# PKP2 V1.04 DRC semantic alignment, 2026-10-13.
# M1 routing PITCH stays 28nm (112nm at4x); cell M1 columns stay42nm.
# M0-M13 corner spacing is Euclidean CORNERTOCORNER, not MAXXY.
# Engineering AREA, array pitches and BSC conservative spacing are retained.
VERSION 5.8 ;
BUSBITCHARS "[]" ;
DIVIDERCHAR "/" ;
USEMINSPACING OBS OFF ;
CLEARANCEMEASURE EUCLIDEAN ;

PROPERTYDEFINITIONS
  LAYER LEF58_BACKSIDE STRING ;
  LAYER LEF58_PITCH STRING ;
  LAYER LEF58_CUTCLASS STRING ;
  LAYER LEF58_SPACINGTABLE STRING ;
  LAYER LEF58_ENCLOSURE STRING ;
  LAYER LEF58_CORNERSPACING STRING ;
  LAYER LEF58_RECTONLY STRING ;
  LAYER LEF58_RIGHTWAYONGRIDONLY STRING ;
  LAYER LEF58_TYPE STRING ;
  LAYER LEF58_SPACING STRING ;
  LAYER LEF58_WIDTH STRING ;
END PROPERTYDEFINITIONS

UNITS
  DATABASE MICRONS 2000 ;
END UNITS
MANUFACTURINGGRID 0.0005 ;

SITE CoreSite
  SIZE 0.042 BY 0.094 ;
  CLASS CORE ;
  SYMMETRY Y ;
END CoreSite

LAYER OVERLAP
  TYPE OVERLAP ;
END OVERLAP

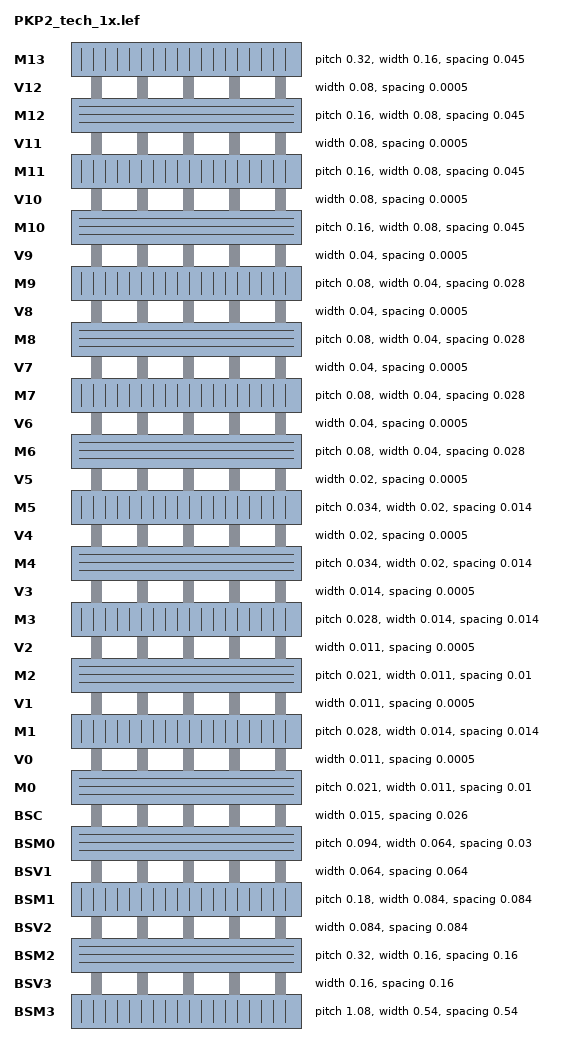
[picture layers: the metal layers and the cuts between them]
LAYER BSM3
  TYPE ROUTING ;
  DIRECTION VERTICAL ;
  PITCH 1.08 ;
  OFFSET 0.0 ;
  WIDTH 0.54 ;
  MINWIDTH 0.54 ;
  # Engineering P&R AREA: square minimum-width backside landing pad.
  AREA 0.2916 ;
  SPACING 0.54 ;
  PROPERTY LEF58_BACKSIDE "BACKSIDE ;" ;
END BSM3

LAYER BSV3
  TYPE CUT ;
  SPACING 0.16 ;
  WIDTH 0.16 ;
  PROPERTY LEF58_BACKSIDE "BACKSIDE ;" ;
  PROPERTY LEF58_CUTCLASS "CUTCLASS PKP2_BSV3 WIDTH 0.16 CUTS 1 ;" ;
  PROPERTY LEF58_SPACINGTABLE "SPACINGTABLE DEFAULT 0.16 CUTCLASS PKP2_BSV3 PKP2_BSV3 0.16 0.16 ;" ;
  PROPERTY LEF58_ENCLOSURE "ENCLOSURE CUTCLASS PKP2_BSV3 ABOVE HORIZONTAL 0 VERTICAL 0 ; ENCLOSURE CUTCLASS PKP2_BSV3 BELOW HORIZONTAL 0 VERTICAL 0.02 ;" ;
END BSV3

LAYER BSM2
  TYPE ROUTING ;
  DIRECTION HORIZONTAL ;
  PITCH 0.32 ;
  OFFSET 0.0 ;
  WIDTH 0.16 ;
  MINWIDTH 0.16 ;
  # Engineering P&R AREA: square minimum-width backside landing pad.
  AREA 0.0256 ;
  SPACING 0.16 ;
  PROPERTY LEF58_BACKSIDE "BACKSIDE ;" ;
END BSM2

LAYER BSV2
  # BSV2_BSM2_EN_1 measures Y enclosure. BELOW is BSM2 in this stack.
  TYPE CUT ;
  SPACING 0.084 ;
  WIDTH 0.084 ;
  PROPERTY LEF58_BACKSIDE "BACKSIDE ;" ;
  PROPERTY LEF58_CUTCLASS "CUTCLASS PKP2_BSV2 WIDTH 0.084 CUTS 1 ;" ;
  PROPERTY LEF58_SPACINGTABLE "SPACINGTABLE DEFAULT 0.084 CUTCLASS PKP2_BSV2 PKP2_BSV2 0.084 0.084 ;" ;
  PROPERTY LEF58_ENCLOSURE "ENCLOSURE CUTCLASS PKP2_BSV2 ABOVE HORIZONTAL 0 VERTICAL 0 ; ENCLOSURE CUTCLASS PKP2_BSV2 BELOW HORIZONTAL 0 VERTICAL 0.01 ;" ;
END BSV2

LAYER BSM1
  TYPE ROUTING ;
  DIRECTION VERTICAL ;
  PITCH 0.18 ;
  OFFSET 0.0 ;
  WIDTH 0.084 ;
  MINWIDTH 0.084 ;
  # Engineering P&R AREA: square minimum-width backside landing pad.
  AREA 0.007056 ;
  SPACING 0.084 ;
  PROPERTY LEF58_BACKSIDE "BACKSIDE ;" ;
END BSM1

LAYER BSV1
  TYPE CUT ;
  SPACING 0.064 ;
  WIDTH 0.064 ;
  PROPERTY LEF58_BACKSIDE "BACKSIDE ;" ;
  PROPERTY LEF58_CUTCLASS "CUTCLASS PKP2_BSV1 WIDTH 0.064 CUTS 1 ;" ;
  PROPERTY LEF58_SPACINGTABLE "SPACINGTABLE DEFAULT 0.064 CUTCLASS PKP2_BSV1 PKP2_BSV1 0.064 0.064 ;" ;
  PROPERTY LEF58_ENCLOSURE "ENCLOSURE CUTCLASS PKP2_BSV1 ABOVE HORIZONTAL 0 VERTICAL 0 ; ENCLOSURE CUTCLASS PKP2_BSV1 BELOW HORIZONTAL 0 VERTICAL 0.005 ;" ;
END BSV1

LAYER BSM0
  TYPE ROUTING ;
  DIRECTION HORIZONTAL ;
  PITCH 0.094 ;
  OFFSET 0.0 ;
  WIDTH 0.064 ;
  MINWIDTH 0.064 ;
  # Engineering P&R AREA: square minimum-width backside landing pad.
  AREA 0.004096 ;
  SPACING 0.03 ;
  PROPERTY LEF58_BACKSIDE "BACKSIDE ;" ;
END BSM0

LAYER BSC
  TYPE CUT ;
  # BSC_S_1/BSC_S_2: conservative maximum of directional spacing limits.
  SPACING 0.026 ;
  WIDTH 0.015 ;
  PROPERTY LEF58_BACKSIDE "BACKSIDE ;" ;
  PROPERTY LEF58_CUTCLASS "CUTCLASS PKP2_BSC WIDTH 0.015 LENGTH 0.016 CUTS 1 ORIENT HORIZONTAL ;" ;
  PROPERTY LEF58_SPACINGTABLE "SPACINGTABLE DEFAULT 0.026 CUTCLASS PKP2_BSC PKP2_BSC 0.026 0.026 ;" ;
  PROPERTY LEF58_ENCLOSURE "ENCLOSURE CUTCLASS PKP2_BSC BELOW HORIZONTAL 0 VERTICAL 0.003 ;" ;
  # BSC_W_1/W_2: 16nm horizontal, 15nm vertical; CT-side connectivity stays in signoff.
END BSC

# BSC_SRAM is defined in the SRAM physical/signoff views, not in the P&R stack.

LAYER M0
  TYPE ROUTING ;
  DIRECTION HORIZONTAL ;
  PITCH 0.021 ;
  OFFSET 0.0155 ;
  WIDTH 0.011 ;
  MINWIDTH 0.011 ;
  # M0_W_2 and M0_A_1: 0.011 x 0.025 is the conservative P&R area.
  AREA 0.000275 ;
  SPACING 0.01 ;
  # M0_S_1/S_2: all-width side/tip tables for PRL>0.
  PROPERTY LEF58_SPACINGTABLE "SPACINGTABLE DIRECTIONALSPANLENGTH PRL 0 SPANLENGTH 0 0.01 ; SPACINGTABLE DIRECTIONALSPANLENGTH WRONGDIRECTION PRL 0 SPANLENGTH 0 0.018 ;" ;
  PROPERTY LEF58_CORNERSPACING "CORNERSPACING CONVEXCORNER CORNERTOCORNER WIDTH 0 SPACING 0.01 ;" ;
  PROPERTY LEF58_RECTONLY "RECTONLY ;" ;
  PROPERTY LEF58_RIGHTWAYONGRIDONLY "RIGHTWAYONGRIDONLY ;" ;
  # Four M0 tracks repeat per 94nm base row; cross-row center spacing is 31nm.
  PROPERTY LEF58_PITCH "PITCH 0.021 FIRSTLASTPITCH 0.0155 ;" ;
END M0

LAYER V0
  # V0_S_1: corner spacing in strictly negative-PRL table entry;
  # PRL>0 uses one manufacturing-grid guard, not a DRC edge minimum.
  TYPE CUT ;
  SPACING 0.0005 ;
  WIDTH 0.011 ;
  PROPERTY LEF58_CUTCLASS "CUTCLASS PKP2_V0 WIDTH 0.011 LENGTH 0.014 CUTS 1 ORIENT HORIZONTAL ;" ;
  # Unclassified via sizes retain a conservative full-spacing fallback.
  PROPERTY LEF58_SPACINGTABLE "SPACINGTABLE DEFAULT 0.011 PRL -0.0005 CUTCLASS PKP2_V0 PKP2_V0 0.011 0.0005 ;" ;
  PROPERTY LEF58_ENCLOSURE "ENCLOSURE CUTCLASS PKP2_V0 BELOW HORIZONTAL 0.003 VERTICAL 0 ; ENCLOSURE CUTCLASS PKP2_V0 ABOVE HORIZONTAL 0 VERTICAL 0.003 ;" ;
END V0

LAYER M1
  TYPE ROUTING ;
  DIRECTION VERTICAL ;
  PITCH 0.028 ;
  OFFSET 0.014 ;
  WIDTH 0.014 ;
  MINWIDTH 0.014 ;
  # M1_A_1, M1_S_2, M1_S_3 and M1_AUX_1
  AREA 0.000504 ;
  SPACING 0.014 ;
  # M1_S_1/S_2: all-width side/tip tables for PRL>0.
  PROPERTY LEF58_SPACINGTABLE "SPACINGTABLE DIRECTIONALSPANLENGTH PRL 0 SPANLENGTH 0 0.014 ; SPACINGTABLE DIRECTIONALSPANLENGTH WRONGDIRECTION PRL 0 SPANLENGTH 0 0.014 ;" ;
  PROPERTY LEF58_CORNERSPACING "CORNERSPACING CONVEXCORNER CORNERTOCORNER WIDTH 0 SPACING 0.024 ;" ;
  PROPERTY LEF58_RECTONLY "RECTONLY ;" ;
END M1

LAYER V1
  # V1_S_1: corner spacing in strictly negative-PRL table entry;
  # PRL>0 uses one manufacturing-grid guard, not a DRC edge minimum.
  TYPE CUT ;
  SPACING 0.0005 ;
  WIDTH 0.011 ;
  PROPERTY LEF58_CUTCLASS "CUTCLASS PKP2_V1 WIDTH 0.011 LENGTH 0.014 CUTS 1 ORIENT HORIZONTAL ;" ;
  # Unclassified via sizes retain a conservative full-spacing fallback.
  PROPERTY LEF58_SPACINGTABLE "SPACINGTABLE DEFAULT 0.01 PRL -0.0005 CUTCLASS PKP2_V1 PKP2_V1 0.01 0.0005 ;" ;
  PROPERTY LEF58_ENCLOSURE "ENCLOSURE CUTCLASS PKP2_V1 BELOW HORIZONTAL 0 VERTICAL 0.005 ; ENCLOSURE CUTCLASS PKP2_V1 ABOVE HORIZONTAL 0.005 VERTICAL 0 ;" ;
END V1

LAYER M2
  TYPE ROUTING ;
  DIRECTION HORIZONTAL ;
  PITCH 0.021 ;
  OFFSET 0.0 ;
  WIDTH 0.011 ;
  MINWIDTH 0.011 ;
  # Engineering P&R AREA: PKP3E width-normalized grouping, with local via floor.
  AREA 0.000504 ;
  # M2_S_2, M2_S_3 and M2_AUX_1
  SPACING 0.01 ;
  # M2_S_1/S_2: all-width side/tip tables for PRL>0.
  PROPERTY LEF58_SPACINGTABLE "SPACINGTABLE DIRECTIONALSPANLENGTH PRL 0 SPANLENGTH 0 0.01 ; SPACINGTABLE DIRECTIONALSPANLENGTH WRONGDIRECTION PRL 0 SPANLENGTH 0 0.014 ;" ;
  PROPERTY LEF58_CORNERSPACING "CORNERSPACING CONVEXCORNER CORNERTOCORNER WIDTH 0 SPACING 0.016 ;" ;
  PROPERTY LEF58_RECTONLY "RECTONLY ;" ;
  PROPERTY LEF58_RIGHTWAYONGRIDONLY "RIGHTWAYONGRIDONLY ;" ;
END M2

LAYER V2
  # V2_S_1: corner spacing in strictly negative-PRL table entry;
  # PRL>0 uses one manufacturing-grid guard, not a DRC edge minimum.
  TYPE CUT ;
  SPACING 0.0005 ;
  WIDTH 0.011 ;
  PROPERTY LEF58_CUTCLASS "CUTCLASS PKP2_V2 WIDTH 0.011 LENGTH 0.014 CUTS 1 ORIENT HORIZONTAL ;" ;
  # Unclassified via sizes retain a conservative full-spacing fallback.
  PROPERTY LEF58_SPACINGTABLE "SPACINGTABLE DEFAULT 0.01 PRL -0.0005 CUTCLASS PKP2_V2 PKP2_V2 0.01 0.0005 ;" ;
  PROPERTY LEF58_ENCLOSURE "ENCLOSURE CUTCLASS PKP2_V2 BELOW HORIZONTAL 0.005 VERTICAL 0 ; ENCLOSURE CUTCLASS PKP2_V2 ABOVE HORIZONTAL 0 VERTICAL 0.005 ;" ;
END V2

LAYER M3
  TYPE ROUTING ;
  DIRECTION VERTICAL ;
  PITCH 0.028 ;
  OFFSET 0.0 ;
  WIDTH 0.014 ;
  MINWIDTH 0.014 ;
  # Engineering P&R AREA: PKP3E width-normalized grouping, with local via floor.
  AREA 0.000504 ;
  # M3_S_2, M3_S_3 and M3_AUX_1
  SPACING 0.014 ;
  # M3_S_1/S_2: all-width side/tip tables for PRL>0.
  PROPERTY LEF58_SPACINGTABLE "SPACINGTABLE DIRECTIONALSPANLENGTH PRL 0 SPANLENGTH 0 0.014 ; SPACINGTABLE DIRECTIONALSPANLENGTH WRONGDIRECTION PRL 0 SPANLENGTH 0 0.02 ;" ;
  PROPERTY LEF58_CORNERSPACING "CORNERSPACING CONVEXCORNER CORNERTOCORNER WIDTH 0 SPACING 0.016 ;" ;
  PROPERTY LEF58_RECTONLY "RECTONLY ;" ;
  PROPERTY LEF58_RIGHTWAYONGRIDONLY "RIGHTWAYONGRIDONLY ;" ;
END M3

LAYER V3
  # V3_S_1: corner spacing in strictly negative-PRL table entry;
  # PRL>0 uses one manufacturing-grid guard, not a DRC edge minimum.
  TYPE CUT ;
  SPACING 0.0005 ;
  WIDTH 0.014 ;
  PROPERTY LEF58_CUTCLASS "CUTCLASS PKP2_V3 WIDTH 0.014 LENGTH 0.02 CUTS 1 ORIENT VERTICAL ;" ;
  # Unclassified via sizes retain a conservative full-spacing fallback.
  PROPERTY LEF58_SPACINGTABLE "SPACINGTABLE DEFAULT 0.014 PRL -0.0005 CUTCLASS PKP2_V3 PKP2_V3 0.014 0.0005 ;" ;
  PROPERTY LEF58_ENCLOSURE "ENCLOSURE CUTCLASS PKP2_V3 BELOW HORIZONTAL 0 VERTICAL 0.005 ; ENCLOSURE CUTCLASS PKP2_V3 ABOVE HORIZONTAL 0.005 VERTICAL 0 ;" ;
END V3

LAYER M4
  TYPE ROUTING ;
  DIRECTION HORIZONTAL ;
  PITCH 0.034 ;
  OFFSET 0.0 ;
  WIDTH 0.02 ;
  MINWIDTH 0.02 ;
  # Engineering P&R AREA: PKP3E width-normalized grouping, with local via floor.
  AREA 0.001 ;
  # M4_S_2, M4_S_3 and M4_AUX_1
  SPACING 0.014 ;
  # M4_S_1/S_2: all-width side/tip tables for PRL>0.
  PROPERTY LEF58_SPACINGTABLE "SPACINGTABLE DIRECTIONALSPANLENGTH PRL 0 SPANLENGTH 0 0.014 ; SPACINGTABLE DIRECTIONALSPANLENGTH WRONGDIRECTION PRL 0 SPANLENGTH 0 0.032 ;" ;
  PROPERTY LEF58_CORNERSPACING "CORNERSPACING CONVEXCORNER CORNERTOCORNER WIDTH 0 SPACING 0.028 ;" ;
  PROPERTY LEF58_RECTONLY "RECTONLY ;" ;
  PROPERTY LEF58_RIGHTWAYONGRIDONLY "RIGHTWAYONGRIDONLY ;" ;
END M4

LAYER V4
  # V4_S_1: corner spacing in strictly negative-PRL table entry;
  # PRL>0 uses one manufacturing-grid guard, not a DRC edge minimum.
  TYPE CUT ;
  SPACING 0.0005 ;
  WIDTH 0.02 ;
  PROPERTY LEF58_CUTCLASS "CUTCLASS PKP2_V4 WIDTH 0.02 CUTS 1 ;" ;
  # Unclassified via sizes retain a conservative full-spacing fallback.
  PROPERTY LEF58_SPACINGTABLE "SPACINGTABLE DEFAULT 0.014 PRL -0.0005 CUTCLASS PKP2_V4 PKP2_V4 0.014 0.0005 ;" ;
  PROPERTY LEF58_ENCLOSURE "ENCLOSURE CUTCLASS PKP2_V4 BELOW HORIZONTAL 0.005 VERTICAL 0 ; ENCLOSURE CUTCLASS PKP2_V4 ABOVE HORIZONTAL 0 VERTICAL 0.005 ;" ;
END V4

LAYER M5
  TYPE ROUTING ;
  DIRECTION VERTICAL ;
  PITCH 0.034 ;
  OFFSET 0.0 ;
  WIDTH 0.02 ;
  MINWIDTH 0.02 ;
  # Engineering P&R AREA: PKP3E width-normalized grouping, with local via floor.
  AREA 0.001 ;
  # M5_S_2, M5_S_3 and M5_AUX_1
  SPACING 0.014 ;
  # M5_S_1/S_2: all-width side/tip tables for PRL>0.
  PROPERTY LEF58_SPACINGTABLE "SPACINGTABLE DIRECTIONALSPANLENGTH PRL 0 SPANLENGTH 0 0.014 ; SPACINGTABLE DIRECTIONALSPANLENGTH WRONGDIRECTION PRL 0 SPANLENGTH 0 0.032 ;" ;
  PROPERTY LEF58_CORNERSPACING "CORNERSPACING CONVEXCORNER CORNERTOCORNER WIDTH 0 SPACING 0.028 ;" ;
  PROPERTY LEF58_RECTONLY "RECTONLY ;" ;
  PROPERTY LEF58_RIGHTWAYONGRIDONLY "RIGHTWAYONGRIDONLY ;" ;
END M5

LAYER V5
  # V5_S_1: corner spacing in strictly negative-PRL table entry;
  # PRL>0 uses one manufacturing-grid guard, not a DRC edge minimum.
  TYPE CUT ;
  SPACING 0.0005 ;
  WIDTH 0.02 ;
  PROPERTY LEF58_CUTCLASS "CUTCLASS PKP2_V5 WIDTH 0.02 LENGTH 0.04 CUTS 1 ORIENT VERTICAL ;" ;
  # Unclassified via sizes retain a conservative full-spacing fallback.
  PROPERTY LEF58_SPACINGTABLE "SPACINGTABLE DEFAULT 0.014 PRL -0.0005 CUTCLASS PKP2_V5 PKP2_V5 0.014 0.0005 ;" ;
  PROPERTY LEF58_ENCLOSURE "ENCLOSURE CUTCLASS PKP2_V5 BELOW HORIZONTAL 0 VERTICAL 0.005 ; ENCLOSURE CUTCLASS PKP2_V5 ABOVE HORIZONTAL 0.005 VERTICAL 0 ;" ;
END V5

LAYER M6
  TYPE ROUTING ;
  DIRECTION HORIZONTAL ;
  PITCH 0.08 ;
  OFFSET 0.0 ;
  WIDTH 0.04 ;
  MINWIDTH 0.04 ;
  # Engineering P&R AREA: PKP3E width-normalized grouping, with local via floor.
  AREA 0.00356 ;
  # M6_S_2, M6_S_3 and M6_AUX_1
  SPACING 0.028 ;
  # M6_S_1/S_2: all-width side/tip tables for PRL>0.
  PROPERTY LEF58_SPACINGTABLE "SPACINGTABLE DIRECTIONALSPANLENGTH PRL 0 SPANLENGTH 0 0.04 ; SPACINGTABLE DIRECTIONALSPANLENGTH WRONGDIRECTION PRL 0 SPANLENGTH 0 0.032 ;" ;
  # Ungated M6_S_1 also checks diagonal corners; combined limit exceeds S_3.
  PROPERTY LEF58_CORNERSPACING "CORNERSPACING CONVEXCORNER CORNERTOCORNER WIDTH 0 SPACING 0.04 ;" ;
  PROPERTY LEF58_RECTONLY "RECTONLY ;" ;
  PROPERTY LEF58_RIGHTWAYONGRIDONLY "RIGHTWAYONGRIDONLY ;" ;
END M6

LAYER V6
  # V6_S_1: corner spacing in strictly negative-PRL table entry;
  # PRL>0 uses one manufacturing-grid guard, not a DRC edge minimum.
  TYPE CUT ;
  SPACING 0.0005 ;
  WIDTH 0.04 ;
  PROPERTY LEF58_CUTCLASS "CUTCLASS PKP2_V6 WIDTH 0.04 CUTS 1 ;" ;
  # Unclassified via sizes retain a conservative full-spacing fallback.
  PROPERTY LEF58_SPACINGTABLE "SPACINGTABLE DEFAULT 0.04 PRL -0.0005 CUTCLASS PKP2_V6 PKP2_V6 0.04 0.0005 ;" ;
  PROPERTY LEF58_ENCLOSURE "ENCLOSURE CUTCLASS PKP2_V6 BELOW HORIZONTAL 0.005 VERTICAL 0 ; ENCLOSURE CUTCLASS PKP2_V6 ABOVE HORIZONTAL 0 VERTICAL 0.005 ;" ;
END V6

LAYER M7
  TYPE ROUTING ;
  DIRECTION VERTICAL ;
  PITCH 0.08 ;
  OFFSET 0.0 ;
  WIDTH 0.04 ;
  MINWIDTH 0.04 ;
  # Engineering P&R AREA: PKP3E width-normalized grouping, with local via floor.
  AREA 0.00356 ;
  # M7_S_2, M7_S_3 and M7_AUX_1
  SPACING 0.028 ;
  # M7_S_1/S_2: all-width side/tip tables for PRL>0.
  PROPERTY LEF58_SPACINGTABLE "SPACINGTABLE DIRECTIONALSPANLENGTH PRL 0 SPANLENGTH 0 0.04 ; SPACINGTABLE DIRECTIONALSPANLENGTH WRONGDIRECTION PRL 0 SPANLENGTH 0 0.032 ;" ;
  # Ungated M7_S_1 also checks diagonal corners; combined limit exceeds S_3.
  PROPERTY LEF58_CORNERSPACING "CORNERSPACING CONVEXCORNER CORNERTOCORNER WIDTH 0 SPACING 0.04 ;" ;
  PROPERTY LEF58_RECTONLY "RECTONLY ;" ;
  PROPERTY LEF58_RIGHTWAYONGRIDONLY "RIGHTWAYONGRIDONLY ;" ;
END M7

LAYER V7
  # V7_S_1: corner spacing in strictly negative-PRL table entry;
  # PRL>0 uses one manufacturing-grid guard, not a DRC edge minimum.
  TYPE CUT ;
  SPACING 0.0005 ;
  WIDTH 0.04 ;
  PROPERTY LEF58_CUTCLASS "CUTCLASS PKP2_V7 WIDTH 0.04 CUTS 1 ;" ;
  # Unclassified via sizes retain a conservative full-spacing fallback.
  PROPERTY LEF58_SPACINGTABLE "SPACINGTABLE DEFAULT 0.04 PRL -0.0005 CUTCLASS PKP2_V7 PKP2_V7 0.04 0.0005 ;" ;
  PROPERTY LEF58_ENCLOSURE "ENCLOSURE CUTCLASS PKP2_V7 BELOW HORIZONTAL 0 VERTICAL 0.005 ; ENCLOSURE CUTCLASS PKP2_V7 ABOVE HORIZONTAL 0.005 VERTICAL 0 ;" ;
END V7

LAYER M8
  TYPE ROUTING ;
  DIRECTION HORIZONTAL ;
  PITCH 0.08 ;
  OFFSET 0.0 ;
  WIDTH 0.04 ;
  MINWIDTH 0.04 ;
  # Engineering P&R AREA: PKP3E width-normalized grouping, with local via floor.
  AREA 0.00356 ;
  # M8_S_2, M8_S_3 and M8_AUX_1
  SPACING 0.028 ;
  # M8_S_1/S_2: all-width side/tip tables for PRL>0.
  PROPERTY LEF58_SPACINGTABLE "SPACINGTABLE DIRECTIONALSPANLENGTH PRL 0 SPANLENGTH 0 0.04 ; SPACINGTABLE DIRECTIONALSPANLENGTH WRONGDIRECTION PRL 0 SPANLENGTH 0 0.032 ;" ;
  # Ungated M8_S_1 also checks diagonal corners; combined limit exceeds S_3.
  PROPERTY LEF58_CORNERSPACING "CORNERSPACING CONVEXCORNER CORNERTOCORNER WIDTH 0 SPACING 0.04 ;" ;
  PROPERTY LEF58_RECTONLY "RECTONLY ;" ;
  PROPERTY LEF58_RIGHTWAYONGRIDONLY "RIGHTWAYONGRIDONLY ;" ;
END M8

LAYER V8
  # V8_S_1: corner spacing in strictly negative-PRL table entry;
  # PRL>0 uses one manufacturing-grid guard, not a DRC edge minimum.
  TYPE CUT ;
  SPACING 0.0005 ;
  WIDTH 0.04 ;
  PROPERTY LEF58_CUTCLASS "CUTCLASS PKP2_V8 WIDTH 0.04 CUTS 1 ;" ;
  # Unclassified via sizes retain a conservative full-spacing fallback.
  PROPERTY LEF58_SPACINGTABLE "SPACINGTABLE DEFAULT 0.04 PRL -0.0005 CUTCLASS PKP2_V8 PKP2_V8 0.04 0.0005 ;" ;
  PROPERTY LEF58_ENCLOSURE "ENCLOSURE CUTCLASS PKP2_V8 BELOW HORIZONTAL 0.005 VERTICAL 0 ; ENCLOSURE CUTCLASS PKP2_V8 ABOVE HORIZONTAL 0 VERTICAL 0.005 ;" ;
END V8

LAYER M9
  TYPE ROUTING ;
  DIRECTION VERTICAL ;
  PITCH 0.08 ;
  OFFSET 0.0 ;
  WIDTH 0.04 ;
  MINWIDTH 0.04 ;
  # Engineering P&R AREA: PKP3E width-normalized grouping, with local via floor.
  AREA 0.00356 ;
  # M9_S_2, M9_S_3 and M9_AUX_1
  SPACING 0.028 ;
  # M9_S_1/S_2: all-width side/tip tables for PRL>0.
  PROPERTY LEF58_SPACINGTABLE "SPACINGTABLE DIRECTIONALSPANLENGTH PRL 0 SPANLENGTH 0 0.04 ; SPACINGTABLE DIRECTIONALSPANLENGTH WRONGDIRECTION PRL 0 SPANLENGTH 0 0.032 ;" ;
  # Ungated M9_S_1 also checks diagonal corners; combined limit exceeds S_3.
  PROPERTY LEF58_CORNERSPACING "CORNERSPACING CONVEXCORNER CORNERTOCORNER WIDTH 0 SPACING 0.04 ;" ;
  PROPERTY LEF58_RECTONLY "RECTONLY ;" ;
  PROPERTY LEF58_RIGHTWAYONGRIDONLY "RIGHTWAYONGRIDONLY ;" ;
END M9

LAYER V9
  # V9_S_1: corner spacing in strictly negative-PRL table entry;
  # PRL>0 uses one manufacturing-grid guard, not a DRC edge minimum.
  TYPE CUT ;
  SPACING 0.0005 ;
  WIDTH 0.04 ;
  PROPERTY LEF58_CUTCLASS "CUTCLASS PKP2_V9 WIDTH 0.04 LENGTH 0.08 CUTS 1 ORIENT VERTICAL ;" ;
  # Unclassified via sizes retain a conservative full-spacing fallback.
  PROPERTY LEF58_SPACINGTABLE "SPACINGTABLE DEFAULT 0.04 PRL -0.0005 CUTCLASS PKP2_V9 PKP2_V9 0.04 0.0005 ;" ;
  PROPERTY LEF58_ENCLOSURE "ENCLOSURE CUTCLASS PKP2_V9 BELOW HORIZONTAL 0 VERTICAL 0 ; ENCLOSURE CUTCLASS PKP2_V9 ABOVE HORIZONTAL 0 VERTICAL 0 ;" ;
END V9

LAYER M10
  TYPE ROUTING ;
  DIRECTION HORIZONTAL ;
  PITCH 0.16 ;
  OFFSET 0.0 ;
  WIDTH 0.08 ;
  MINWIDTH 0.08 ;
  # Engineering P&R AREA: PKP3E width-normalized grouping, with local via floor.
  AREA 0.0128 ;
  # M10_S_2, M10_S_3 and M10_AUX_1
  SPACING 0.045 ;
  # M10_S_1/S_2: all-width side/tip tables for PRL>0.
  PROPERTY LEF58_SPACINGTABLE "SPACINGTABLE DIRECTIONALSPANLENGTH PRL 0 SPANLENGTH 0 0.08 ; SPACINGTABLE DIRECTIONALSPANLENGTH WRONGDIRECTION PRL 0 SPANLENGTH 0 0.05 ;" ;
  # Ungated M10_S_1 also checks diagonal corners; combined limit exceeds S_3.
  PROPERTY LEF58_CORNERSPACING "CORNERSPACING CONVEXCORNER CORNERTOCORNER WIDTH 0 SPACING 0.08 ;" ;
  PROPERTY LEF58_RECTONLY "RECTONLY ;" ;
  PROPERTY LEF58_RIGHTWAYONGRIDONLY "RIGHTWAYONGRIDONLY ;" ;
END M10

LAYER V10
  # V10_S_1: corner spacing in strictly negative-PRL table entry;
  # PRL>0 uses one manufacturing-grid guard, not a DRC edge minimum.
  TYPE CUT ;
  SPACING 0.0005 ;
  WIDTH 0.08 ;
  PROPERTY LEF58_CUTCLASS "CUTCLASS PKP2_V10 WIDTH 0.08 CUTS 1 ;" ;
  # Unclassified via sizes retain a conservative full-spacing fallback.
  PROPERTY LEF58_SPACINGTABLE "SPACINGTABLE DEFAULT 0.08 PRL -0.0005 CUTCLASS PKP2_V10 PKP2_V10 0.08 0.0005 ;" ;
  PROPERTY LEF58_ENCLOSURE "ENCLOSURE CUTCLASS PKP2_V10 BELOW HORIZONTAL 0 VERTICAL 0 ; ENCLOSURE CUTCLASS PKP2_V10 ABOVE HORIZONTAL 0 VERTICAL 0 ;" ;
END V10

LAYER M11
  TYPE ROUTING ;
  DIRECTION VERTICAL ;
  PITCH 0.16 ;
  OFFSET 0.0 ;
  WIDTH 0.08 ;
  MINWIDTH 0.08 ;
  # Engineering P&R AREA: PKP3E width-normalized grouping, with local via floor.
  AREA 0.0128 ;
  # M11_S_2, M11_S_3 and M11_AUX_1
  SPACING 0.045 ;
  # M11_S_1/S_2: all-width side/tip tables for PRL>0.
  PROPERTY LEF58_SPACINGTABLE "SPACINGTABLE DIRECTIONALSPANLENGTH PRL 0 SPANLENGTH 0 0.08 ; SPACINGTABLE DIRECTIONALSPANLENGTH WRONGDIRECTION PRL 0 SPANLENGTH 0 0.05 ;" ;
  # Ungated M11_S_1 also checks diagonal corners; combined limit exceeds S_3.
  PROPERTY LEF58_CORNERSPACING "CORNERSPACING CONVEXCORNER CORNERTOCORNER WIDTH 0 SPACING 0.08 ;" ;
  PROPERTY LEF58_RECTONLY "RECTONLY ;" ;
  PROPERTY LEF58_RIGHTWAYONGRIDONLY "RIGHTWAYONGRIDONLY ;" ;
END M11

LAYER V11
  # V11_S_1: corner spacing in strictly negative-PRL table entry;
  # PRL>0 uses one manufacturing-grid guard, not a DRC edge minimum.
  TYPE CUT ;
  SPACING 0.0005 ;
  WIDTH 0.08 ;
  PROPERTY LEF58_CUTCLASS "CUTCLASS PKP2_V11 WIDTH 0.08 CUTS 1 ;" ;
  # Unclassified via sizes retain a conservative full-spacing fallback.
  PROPERTY LEF58_SPACINGTABLE "SPACINGTABLE DEFAULT 0.08 PRL -0.0005 CUTCLASS PKP2_V11 PKP2_V11 0.08 0.0005 ;" ;
  PROPERTY LEF58_ENCLOSURE "ENCLOSURE CUTCLASS PKP2_V11 BELOW HORIZONTAL 0 VERTICAL 0 ; ENCLOSURE CUTCLASS PKP2_V11 ABOVE HORIZONTAL 0 VERTICAL 0 ;" ;
END V11

LAYER M12
  TYPE ROUTING ;
  DIRECTION HORIZONTAL ;
  PITCH 0.16 ;
  OFFSET 0.0 ;
  WIDTH 0.08 ;
  MINWIDTH 0.08 ;
  # Engineering P&R AREA: PKP3E width-normalized grouping, with local via floor.
  AREA 0.0128 ;
  # M12_S_2, M12_S_3 and M12_AUX_1
  SPACING 0.045 ;
  # M12_S_1/S_2: all-width side/tip tables for PRL>0.
  PROPERTY LEF58_SPACINGTABLE "SPACINGTABLE DIRECTIONALSPANLENGTH PRL 0 SPANLENGTH 0 0.08 ; SPACINGTABLE DIRECTIONALSPANLENGTH WRONGDIRECTION PRL 0 SPANLENGTH 0 0.05 ;" ;
  # Ungated M12_S_1 also checks diagonal corners; combined limit exceeds S_3.
  PROPERTY LEF58_CORNERSPACING "CORNERSPACING CONVEXCORNER CORNERTOCORNER WIDTH 0 SPACING 0.08 ;" ;
  PROPERTY LEF58_RECTONLY "RECTONLY ;" ;
  PROPERTY LEF58_RIGHTWAYONGRIDONLY "RIGHTWAYONGRIDONLY ;" ;
END M12

LAYER V12
  # V12_S_1: corner spacing in strictly negative-PRL table entry;
  # PRL>0 uses one manufacturing-grid guard, not a DRC edge minimum.
  TYPE CUT ;
  SPACING 0.0005 ;
  WIDTH 0.08 ;
  PROPERTY LEF58_CUTCLASS "CUTCLASS PKP2_V12 WIDTH 0.08 LENGTH 0.16 CUTS 1 ORIENT HORIZONTAL ;" ;
  # Unclassified via sizes retain a conservative full-spacing fallback.
  PROPERTY LEF58_SPACINGTABLE "SPACINGTABLE DEFAULT 0.08 PRL -0.0005 CUTCLASS PKP2_V12 PKP2_V12 0.08 0.0005 ;" ;
  PROPERTY LEF58_ENCLOSURE "ENCLOSURE CUTCLASS PKP2_V12 BELOW HORIZONTAL 0 VERTICAL 0 ; ENCLOSURE CUTCLASS PKP2_V12 ABOVE HORIZONTAL 0 VERTICAL 0 ;" ;
END V12

LAYER M13
  TYPE ROUTING ;
  DIRECTION VERTICAL ;
  PITCH 0.32 ;
  OFFSET 0.0 ;
  WIDTH 0.16 ;
  MINWIDTH 0.16 ;
  # Engineering P&R AREA: PKP3E width-normalized grouping, with local via floor.
  AREA 0.04272 ;
  # M13_S_2, M13_S_3 and M13_AUX_1
  SPACING 0.045 ;
  # M13_S_1/S_2: all-width side/tip tables for PRL>0.
  PROPERTY LEF58_SPACINGTABLE "SPACINGTABLE DIRECTIONALSPANLENGTH PRL 0 SPANLENGTH 0 0.16 ; SPACINGTABLE DIRECTIONALSPANLENGTH WRONGDIRECTION PRL 0 SPANLENGTH 0 0.05 ;" ;
  # Ungated M13_S_1 also checks diagonal corners; combined limit exceeds S_3.
  PROPERTY LEF58_CORNERSPACING "CORNERSPACING CONVEXCORNER CORNERTOCORNER WIDTH 0 SPACING 0.16 ;" ;
  PROPERTY LEF58_RECTONLY "RECTONLY ;" ;
  PROPERTY LEF58_RIGHTWAYONGRIDONLY "RIGHTWAYONGRIDONLY ;" ;
END M13

# Fixed single-cut default vias for P&R.  Metal rectangles satisfy the
# direction-specific exact-width/enclosure rules in the Calibre deck.
VIA BSV1_DEFAULT DEFAULT
  LAYER BSM0 ;
    RECT -0.032 -0.032 0.032 0.032 ;
  LAYER BSV1 ;
    RECT -0.032 -0.032 0.032 0.032 ;
  LAYER BSM1 ;
    RECT -0.042 -0.042 0.042 0.042 ;
END BSV1_DEFAULT

VIA BSV2_DEFAULT DEFAULT
  LAYER BSM1 ;
    RECT -0.042 -0.042 0.042 0.042 ;
  LAYER BSV2 ;
    RECT -0.042 -0.042 0.042 0.042 ;
  LAYER BSM2 ;
    RECT -0.08 -0.08 0.08 0.08 ;
END BSV2_DEFAULT

VIA BSV3_DEFAULT DEFAULT
  LAYER BSM2 ;
    RECT -0.08 -0.08 0.08 0.08 ;
  LAYER BSV3 ;
    RECT -0.08 -0.08 0.08 0.08 ;
  LAYER BSM3 ;
    RECT -0.27 -0.27 0.27 0.27 ;
END BSV3_DEFAULT

VIA V0_DEFAULT DEFAULT
  LAYER M0 ;
    RECT -0.013 -0.0055 0.013 0.0055 ;
  LAYER V0 ;
    RECT -0.007 -0.0055 0.007 0.0055 ;
  LAYER M1 ;
    RECT -0.007 -0.018 0.007 0.018 ;
END V0_DEFAULT

VIA V1_DEFAULT DEFAULT
  LAYER M1 ;
    RECT -0.007 -0.018 0.007 0.018 ;
  LAYER V1 ;
    RECT -0.007 -0.0055 0.007 0.0055 ;
  LAYER M2 ;
    RECT -0.023 -0.0055 0.023 0.0055 ;
END V1_DEFAULT

VIA V2_DEFAULT DEFAULT
  LAYER M2 ;
    RECT -0.023 -0.0055 0.023 0.0055 ;
  LAYER V2 ;
    RECT -0.007 -0.0055 0.007 0.0055 ;
  LAYER M3 ;
    RECT -0.007 -0.018 0.007 0.018 ;
END V2_DEFAULT

VIA V3_DEFAULT DEFAULT
  LAYER M3 ;
    RECT -0.007 -0.018 0.007 0.018 ;
  LAYER V3 ;
    RECT -0.007 -0.01 0.007 0.01 ;
  LAYER M4 ;
    RECT -0.025 -0.01 0.025 0.01 ;
END V3_DEFAULT

VIA V4_DEFAULT DEFAULT
  LAYER M4 ;
    RECT -0.025 -0.01 0.025 0.01 ;
  LAYER V4 ;
    RECT -0.01 -0.01 0.01 0.01 ;
  LAYER M5 ;
    RECT -0.01 -0.025 0.01 0.025 ;
END V4_DEFAULT

VIA V5_DEFAULT DEFAULT
  LAYER M5 ;
    RECT -0.01 -0.025 0.01 0.025 ;
  LAYER V5 ;
    RECT -0.01 -0.02 0.01 0.02 ;
  LAYER M6 ;
    RECT -0.0445 -0.02 0.0445 0.02 ;
END V5_DEFAULT

VIA V6_DEFAULT DEFAULT
  LAYER M6 ;
    RECT -0.0445 -0.02 0.0445 0.02 ;
  LAYER V6 ;
    RECT -0.02 -0.02 0.02 0.02 ;
  LAYER M7 ;
    RECT -0.02 -0.0445 0.02 0.0445 ;
END V6_DEFAULT

VIA V7_DEFAULT DEFAULT
  LAYER M7 ;
    RECT -0.02 -0.0445 0.02 0.0445 ;
  LAYER V7 ;
    RECT -0.02 -0.02 0.02 0.02 ;
  LAYER M8 ;
    RECT -0.0445 -0.02 0.0445 0.02 ;
END V7_DEFAULT

VIA V8_DEFAULT DEFAULT
  LAYER M8 ;
    RECT -0.0445 -0.02 0.0445 0.02 ;
  LAYER V8 ;
    RECT -0.02 -0.02 0.02 0.02 ;
  LAYER M9 ;
    RECT -0.02 -0.0445 0.02 0.0445 ;
END V8_DEFAULT

VIA V9_DEFAULT DEFAULT
  LAYER M9 ;
    RECT -0.02 -0.0445 0.02 0.0445 ;
  LAYER V9 ;
    RECT -0.02 -0.04 0.02 0.04 ;
  LAYER M10 ;
    RECT -0.08 -0.04 0.08 0.04 ;
END V9_DEFAULT

VIA V10_DEFAULT DEFAULT
  LAYER M10 ;
    RECT -0.08 -0.04 0.08 0.04 ;
  LAYER V10 ;
    RECT -0.04 -0.04 0.04 0.04 ;
  LAYER M11 ;
    RECT -0.04 -0.08 0.04 0.08 ;
END V10_DEFAULT

VIA V11_DEFAULT DEFAULT
  LAYER M11 ;
    RECT -0.04 -0.08 0.04 0.08 ;
  LAYER V11 ;
    RECT -0.04 -0.04 0.04 0.04 ;
  LAYER M12 ;
    RECT -0.08 -0.04 0.08 0.04 ;
END V11_DEFAULT

VIA V12_DEFAULT DEFAULT
  LAYER M12 ;
    RECT -0.08 -0.04 0.08 0.04 ;
  LAYER V12 ;
    RECT -0.08 -0.04 0.08 0.04 ;
  LAYER M13 ;
    RECT -0.08 -0.1335 0.08 0.1335 ;
END V12_DEFAULT

VIARULE BSM0_BSM1 GENERATE
  LAYER BSM0 ;
    ENCLOSURE 0 0 ;
  LAYER BSM1 ;
    ENCLOSURE 0.01 0.01 ;
  LAYER BSV1 ;
    RECT -0.032 -0.032 0.032 0.032 ;
    SPACING 0.128 BY 0.128 ;
END BSM0_BSM1

VIARULE BSM1_BSM2 GENERATE
  LAYER BSM1 ;
    ENCLOSURE 0 0 ;
  LAYER BSM2 ;
    ENCLOSURE 0.038 0.038 ;
  LAYER BSV2 ;
    RECT -0.042 -0.042 0.042 0.042 ;
    SPACING 0.168 BY 0.168 ;
END BSM1_BSM2

VIARULE BSM2_BSM3 GENERATE
  LAYER BSM2 ;
    ENCLOSURE 0 0 ;
  LAYER BSM3 ;
    ENCLOSURE 0.19 0.19 ;
  LAYER BSV3 ;
    RECT -0.08 -0.08 0.08 0.08 ;
    SPACING 0.32 BY 0.32 ;
END BSM2_BSM3

VIARULE M1_M0 GENERATE
  LAYER M0 ;
    ENCLOSURE 0.006 0 ;
    WIDTH 0.011 TO 0.011 ;
  LAYER M1 ;
    ENCLOSURE 0.0125 0 ;
    WIDTH 0.014 TO 0.014 ;
  LAYER V0 ;
    RECT -0.007 -0.0055 0.007 0.0055 ;
    SPACING 0.025 BY 0.022 ;
END M1_M0

VIARULE M2_M1 GENERATE
  LAYER M1 ;
    ENCLOSURE 0.0125 0 ;
    WIDTH 0.014 TO 0.014 ;
  LAYER M2 ;
    ENCLOSURE 0.016 0 ;
    WIDTH 0.011 TO 0.011 ;
  LAYER V1 ;
    RECT -0.007 -0.0055 0.007 0.0055 ;
    SPACING 0.024 BY 0.021 ;
END M2_M1

VIARULE M3_M2 GENERATE
  LAYER M2 ;
    ENCLOSURE 0.016 0 ;
    WIDTH 0.011 TO 0.011 ;
  LAYER M3 ;
    ENCLOSURE 0.0125 0 ;
    WIDTH 0.014 TO 0.014 ;
  LAYER V2 ;
    RECT -0.007 -0.0055 0.007 0.0055 ;
    SPACING 0.024 BY 0.021 ;
END M3_M2

VIARULE M4_M3 GENERATE
  LAYER M3 ;
    ENCLOSURE 0.008 0 ;
    WIDTH 0.014 TO 0.014 ;
  LAYER M4 ;
    ENCLOSURE 0.018 0 ;
    WIDTH 0.02 TO 0.02 ;
  LAYER V3 ;
    RECT -0.007 -0.01 0.007 0.01 ;
    SPACING 0.028 BY 0.034 ;
END M4_M3

VIARULE M5_M4 GENERATE
  LAYER M4 ;
    ENCLOSURE 0.015 0 ;
    WIDTH 0.02 TO 0.02 ;
  LAYER M5 ;
    ENCLOSURE 0.015 0 ;
    WIDTH 0.02 TO 0.02 ;
  LAYER V4 ;
    RECT -0.01 -0.01 0.01 0.01 ;
    SPACING 0.034 BY 0.034 ;
END M5_M4

VIARULE M6_M5 GENERATE
  LAYER M5 ;
    ENCLOSURE 0.005 0 ;
    WIDTH 0.02 TO 0.02 ;
  LAYER M6 ;
    ENCLOSURE 0.0345 0 ;
    WIDTH 0.04 TO 0.04 ;
  LAYER V5 ;
    RECT -0.01 -0.02 0.01 0.02 ;
    SPACING 0.034 BY 0.054 ;
END M6_M5

VIARULE M7_M6 GENERATE
  LAYER M6 ;
    ENCLOSURE 0.0245 0 ;
    WIDTH 0.04 TO 0.04 ;
  LAYER M7 ;
    ENCLOSURE 0.0245 0 ;
    WIDTH 0.04 TO 0.04 ;
  LAYER V6 ;
    RECT -0.02 -0.02 0.02 0.02 ;
    SPACING 0.08 BY 0.08 ;
END M7_M6

VIARULE M8_M7 GENERATE
  LAYER M7 ;
    ENCLOSURE 0.0245 0 ;
    WIDTH 0.04 TO 0.04 ;
  LAYER M8 ;
    ENCLOSURE 0.0245 0 ;
    WIDTH 0.04 TO 0.04 ;
  LAYER V7 ;
    RECT -0.02 -0.02 0.02 0.02 ;
    SPACING 0.08 BY 0.08 ;
END M8_M7

VIARULE M9_M8 GENERATE
  LAYER M8 ;
    ENCLOSURE 0.0245 0 ;
    WIDTH 0.04 TO 0.04 ;
  LAYER M9 ;
    ENCLOSURE 0.0245 0 ;
    WIDTH 0.04 TO 0.04 ;
  LAYER V8 ;
    RECT -0.02 -0.02 0.02 0.02 ;
    SPACING 0.08 BY 0.08 ;
END M9_M8

VIARULE M10_M9 GENERATE
  LAYER M9 ;
    ENCLOSURE 0.0045 0 ;
    WIDTH 0.04 TO 0.04 ;
  LAYER M10 ;
    ENCLOSURE 0.06 0 ;
    WIDTH 0.08 TO 0.08 ;
  LAYER V9 ;
    RECT -0.02 -0.04 0.02 0.04 ;
    SPACING 0.08 BY 0.12 ;
END M10_M9

VIARULE M11_M10 GENERATE
  LAYER M10 ;
    ENCLOSURE 0.04 0 ;
    WIDTH 0.08 TO 0.08 ;
  LAYER M11 ;
    ENCLOSURE 0.04 0 ;
    WIDTH 0.08 TO 0.08 ;
  LAYER V10 ;
    RECT -0.04 -0.04 0.04 0.04 ;
    SPACING 0.16 BY 0.16 ;
END M11_M10

VIARULE M12_M11 GENERATE
  LAYER M11 ;
    ENCLOSURE 0.04 0 ;
    WIDTH 0.08 TO 0.08 ;
  LAYER M12 ;
    ENCLOSURE 0.04 0 ;
    WIDTH 0.08 TO 0.08 ;
  LAYER V11 ;
    RECT -0.04 -0.04 0.04 0.04 ;
    SPACING 0.16 BY 0.16 ;
END M12_M11

VIARULE M13_M12 GENERATE
  LAYER M12 ;
    ENCLOSURE 0 0 ;
    WIDTH 0.08 TO 0.08 ;
  LAYER M13 ;
    ENCLOSURE 0.0935 0 ;
    WIDTH 0.16 TO 0.16 ;
  LAYER V12 ;
    RECT -0.08 -0.04 0.08 0.04 ;
    SPACING 0.24 BY 0.16 ;
END M13_M12

END LIBRARY
